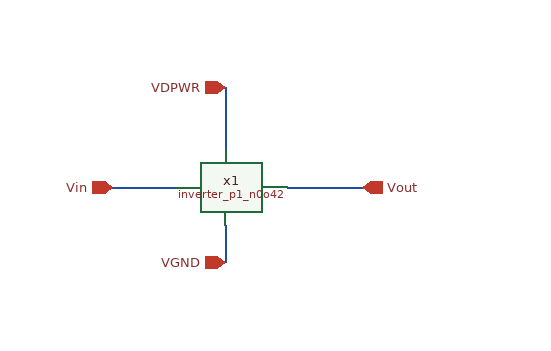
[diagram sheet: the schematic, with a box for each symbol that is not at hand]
v {xschem version=3.4.7 file_version=1.2}
G {}
K {}
V {}
S {}
E {}
N 0 -80 0 -30 {lab=VDPWR}
N 50 0 110 0 {lab=Vout}
N 0 30 0 60 {lab=VGND}
N -90 0 -40 0 {lab=Vin}
C {opin.sym} 110 0 0 0 {name=p5 lab=Vout}
C {ipin.sym} -90 0 0 0 {name=p6 lab=Vin}
C {iopin.sym} 0 -80 0 0 {name=p7 lab=VDPWR}
C {iopin.sym} 0 60 0 0 {name=p8 lab=VGND}
C {/foss/designs/analog-circuit-design/sky25a-TIQ_ADC/xschem/INVERTER_SIZES/inverter_p1_n0o42.sym} 0 0 0 0 {name=x1}
